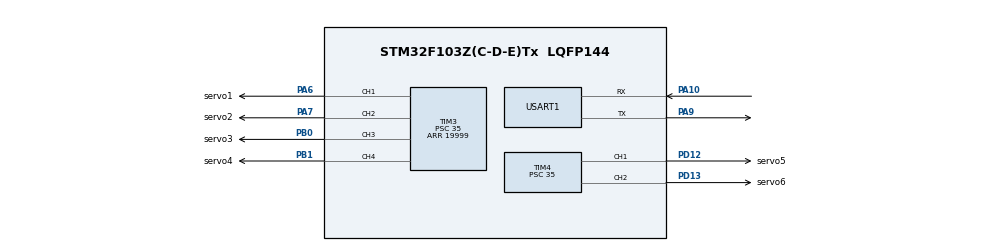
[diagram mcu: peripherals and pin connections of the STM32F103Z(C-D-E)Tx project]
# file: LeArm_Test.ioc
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Mcu.Family=STM32F1
Mcu.Name=STM32F103Z(C-D-E)Tx
Mcu.Package=LQFP144
NVIC.PriorityGroup=NVIC_PRIORITYGROUP_4
NVIC.USART1_IRQn=true\:0\:0\:false\:false\:true\:true\:true
OSC_IN.Mode=HSE-External-Oscillator
OSC_IN.Signal=RCC_OSC_IN
OSC_OUT.Mode=HSE-External-Oscillator
OSC_OUT.Signal=RCC_OSC_OUT
PA10.Mode=Asynchronous
PA10.Signal=USART1_RX
PA13.Mode=Serial_Wire
PA13.Signal=SYS_JTMS-SWDIO
PA14.Mode=Serial_Wire
PA14.Signal=SYS_JTCK-SWCLK
PA6.GPIO_Label=servo1
PA6.Signal=S_TIM3_CH1
PA7.GPIO_Label=servo2
PA7.Signal=S_TIM3_CH2
PA9.Mode=Asynchronous
PA9.Signal=USART1_TX
PB0.GPIO_Label=servo3
PB0.Signal=S_TIM3_CH3
PB1.GPIO_Label=servo4
PB1.Signal=S_TIM3_CH4
PD12.GPIO_Label=servo5
PD12.Signal=S_TIM4_CH1
PD13.GPIO_Label=servo6
PD13.Signal=S_TIM4_CH2
ProjectManager.HeapSize=0x200
ProjectManager.StackSize=0x400
ProjectManager.TargetToolchain=MDK-ARM V5.32
RCC.AHBCLKDivider=RCC_SYSCLK_DIV2
RCC.AHBFreq_Value=36000000
RCC.APB1Freq_Value=36000000
RCC.APB1TimFreq_Value=36000000
RCC.APB2Freq_Value=36000000
RCC.APB2TimFreq_Value=36000000
RCC.HCLKFreq_Value=36000000
RCC.PLLMUL=RCC_PLL_MUL9
RCC.PLLSourceVirtual=RCC_PLLSOURCE_HSE
RCC.SYSCLKFreq_VALUE=72000000
RCC.SYSCLKSource=RCC_SYSCLKSOURCE_PLLCLK
RCC.USBFreq_Value=72000000
SH.S_TIM3_CH1.0=TIM3_CH1,PWM Generation1 CH1
SH.S_TIM3_CH2.0=TIM3_CH2,PWM Generation2 CH2
SH.S_TIM3_CH3.0=TIM3_CH3,PWM Generation3 CH3
SH.S_TIM3_CH4.0=TIM3_CH4,PWM Generation4 CH4
SH.S_TIM4_CH1.0=TIM4_CH1,PWM Generation1 CH1
SH.S_TIM4_CH2.0=TIM4_CH2,PWM Generation2 CH2
TIM3.Channel-PWM\ Generation1\ CH1=TIM_CHANNEL_1
TIM3.Channel-PWM\ Generation2\ CH2=TIM_CHANNEL_2
TIM3.Channel-PWM\ Generation3\ CH3=TIM_CHANNEL_3
TIM3.Channel-PWM\ Generation4\ CH4=TIM_CHANNEL_4
TIM3.Period=19999
TIM3.Prescaler=35
TIM3.Pulse-PWM\ Generation1\ CH1=1400
TIM3.Pulse-PWM\ Generation2\ CH2=1500
TIM3.Pulse-PWM\ Generation3\ CH3=1056
TIM3.Pulse-PWM\ Generation4\ CH4=1056
TIM4.Channel-PWM\ Generation1\ CH1=TIM_CHANNEL_1
TIM4.Channel-PWM\ Generation2\ CH2=TIM_CHANNEL_2
TIM4.Period=19999
TIM4.Prescaler=35
TIM4.Pulse-PWM\ Generation1\ CH1=1500
TIM4.Pulse-PWM\ Generation2\ CH2=1500
USART1.VirtualMode=VM_ASYNC
VP_TIM3_VS_ClockSourceINT.Mode=Internal
VP_TIM4_VS_ClockSourceINT.Mode=Internal
board=custom

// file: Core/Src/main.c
/* USER CODE BEGIN Header */
/**
  ******************************************************************************
  * @file           : main.c
  * @brief          : Main program body
  ******************************************************************************
  * @attention
  *
  * <h2><center>&copy; Copyright (c) 2026 STMicroelectronics.
  * All rights reserved.</center></h2>
  *
  * This software component is licensed by ST under BSD 3-Clause license,
  * the "License"; You may not use this file except in compliance with the
  * License. You may obtain a copy of the License at:
  *                        opensource.org/licenses/BSD-3-Clause
  *
  ******************************************************************************
  */
/* USER CODE END Header */
#include "main.h"

/* USER CODE BEGIN Includes */
#include "learm_protocol.h"
#include "learm_servo.h"
/* USER CODE END Includes */

/* USER CODE BEGIN PD */
#define LEARM_SERVO_UPDATE_MS  20U
#define LEARM_PWM_TICK_HZ      1000000U
/* USER CODE END PD */

TIM_HandleTypeDef htim3;
TIM_HandleTypeDef htim4;

UART_HandleTypeDef huart1;

void SystemClock_Config(void);
static void MX_GPIO_Init(void);
static void MX_TIM3_Init(void);
static void MX_TIM4_Init(void);
static void MX_USART1_UART_Init(void);
static uint32_t LeArm_GetApb1TimerPrescaler(void);

int main(void)
{
  /* USER CODE BEGIN 1 */
  uint32_t lastServoTick;
  /* USER CODE END 1 */

  /* MCU Configuration--------------------------------------------------------*/

  /* Reset of all peripherals, Initializes the Flash interface and the Systick. */
  HAL_Init();

  /* Configure the system clock */
  SystemClock_Config();

  /* Initialize all configured peripherals */
  MX_GPIO_Init();
  MX_USART1_UART_Init();
  MX_TIM3_Init();
  MX_TIM4_Init();
  /* USER CODE BEGIN 2 */
  LeArm_ServoInit();
  LeArm_ProtocolInit(&huart1);
  lastServoTick = HAL_GetTick();
  /* USER CODE END 2 */

  /* Infinite loop */
  while (1)
  {

    /* USER CODE BEGIN 3 */
    LeArm_ProtocolTask();

    if ((uint32_t)(HAL_GetTick() - lastServoTick) >= LEARM_SERVO_UPDATE_MS)
    {
      lastServoTick += LEARM_SERVO_UPDATE_MS;
      LeArm_ServoUpdate20ms();
    }
  }
  /* USER CODE END 3 */
}

static uint32_t LeArm_GetApb1TimerPrescaler(void)
{
  uint32_t timerClockHz = HAL_RCC_GetPCLK1Freq();

  /* STM32F1 timers run at twice PCLK1 whenever APB1 is prescaled. */
  if ((RCC->CFGR & RCC_CFGR_PPRE1) != 0U)
  {
    timerClockHz *= 2U;
  }

  if ((timerClockHz < LEARM_PWM_TICK_HZ) ||
    ((timerClockHz % LEARM_PWM_TICK_HZ) != 0U))
  {
    Error_Handler();
  }

  return (timerClockHz / LEARM_PWM_TICK_HZ) - 1U;
}

void SystemClock_Config(void)
{
  RCC_OscInitTypeDef RCC_OscInitStruct = {0};
  RCC_ClkInitTypeDef RCC_ClkInitStruct = {0};

  /** Initializes the RCC Oscillators according to the specified parameters
  * in the RCC_OscInitTypeDef structure.
  */
  RCC_OscInitStruct.OscillatorType = RCC_OSCILLATORTYPE_HSE;
  RCC_OscInitStruct.HSEState = RCC_HSE_ON;
  RCC_OscInitStruct.HSEPredivValue = RCC_HSE_PREDIV_DIV1;
  RCC_OscInitStruct.HSIState = RCC_HSI_ON;
  RCC_OscInitStruct.PLL.PLLState = RCC_PLL_ON;
  RCC_OscInitStruct.PLL.PLLSource = RCC_PLLSOURCE_HSE;
  RCC_OscInitStruct.PLL.PLLMUL = RCC_PLL_MUL9;
  if (HAL_RCC_OscConfig(&RCC_OscInitStruct) != HAL_OK)
  {
    /* Keep the PWM outputs available on boards with a missing or failed HSE. */
    RCC_OscInitStruct = (RCC_OscInitTypeDef){0};
    RCC_OscInitStruct.OscillatorType = RCC_OSCILLATORTYPE_HSE | RCC_OSCILLATORTYPE_HSI;
    RCC_OscInitStruct.HSEState = RCC_HSE_OFF;
    RCC_OscInitStruct.HSIState = RCC_HSI_ON;
    RCC_OscInitStruct.HSICalibrationValue = RCC_HSICALIBRATION_DEFAULT;
    RCC_OscInitStruct.PLL.PLLState = RCC_PLL_OFF;
    if (HAL_RCC_OscConfig(&RCC_OscInitStruct) != HAL_OK)
    {
      Error_Handler();
    }

    RCC_ClkInitStruct = (RCC_ClkInitTypeDef){0};
    RCC_ClkInitStruct.ClockType = RCC_CLOCKTYPE_HCLK | RCC_CLOCKTYPE_SYSCLK |
      RCC_CLOCKTYPE_PCLK1 | RCC_CLOCKTYPE_PCLK2;
    RCC_ClkInitStruct.SYSCLKSource = RCC_SYSCLKSOURCE_HSI;
    RCC_ClkInitStruct.AHBCLKDivider = RCC_SYSCLK_DIV1;
    RCC_ClkInitStruct.APB1CLKDivider = RCC_HCLK_DIV1;
    RCC_ClkInitStruct.APB2CLKDivider = RCC_HCLK_DIV1;
    if (HAL_RCC_ClockConfig(&RCC_ClkInitStruct, FLASH_LATENCY_0) != HAL_OK)
    {
      Error_Handler();
    }
    return;
  }
  /** Initializes the CPU, AHB and APB buses clocks
  */
  RCC_ClkInitStruct.ClockType = RCC_CLOCKTYPE_HCLK|RCC_CLOCKTYPE_SYSCLK
                              |RCC_CLOCKTYPE_PCLK1|RCC_CLOCKTYPE_PCLK2;
  RCC_ClkInitStruct.SYSCLKSource = RCC_SYSCLKSOURCE_PLLCLK;
  RCC_ClkInitStruct.AHBCLKDivider = RCC_SYSCLK_DIV2;
  RCC_ClkInitStruct.APB1CLKDivider = RCC_HCLK_DIV1;
  RCC_ClkInitStruct.APB2CLKDivider = RCC_HCLK_DIV1;

  if (HAL_RCC_ClockConfig(&RCC_ClkInitStruct, FLASH_LATENCY_2) != HAL_OK)
  {
    Error_Handler();
  }
}

static void MX_TIM3_Init(void)
{

  TIM_ClockConfigTypeDef sClockSourceConfig = {0};
  TIM_MasterConfigTypeDef sMasterConfig = {0};
  TIM_OC_InitTypeDef sConfigOC = {0};

  htim3.Instance = TIM3;
  htim3.Init.Prescaler = LeArm_GetApb1TimerPrescaler();
  htim3.Init.CounterMode = TIM_COUNTERMODE_UP;
  htim3.Init.Period = 19999;
  htim3.Init.ClockDivision = TIM_CLOCKDIVISION_DIV1;
  htim3.Init.AutoReloadPreload = TIM_AUTORELOAD_PRELOAD_DISABLE;
  if (HAL_TIM_Base_Init(&htim3) != HAL_OK)
  {
    Error_Handler();
  }
  sClockSourceConfig.ClockSource = TIM_CLOCKSOURCE_INTERNAL;
  if (HAL_TIM_ConfigClockSource(&htim3, &sClockSourceConfig) != HAL_OK)
  {
    Error_Handler();
  }
  if (HAL_TIM_PWM_Init(&htim3) != HAL_OK)
  {
    Error_Handler();
  }
  sMasterConfig.MasterOutputTrigger = TIM_TRGO_RESET;
  sMasterConfig.MasterSlaveMode = TIM_MASTERSLAVEMODE_DISABLE;
  if (HAL_TIMEx_MasterConfigSynchronization(&htim3, &sMasterConfig) != HAL_OK)
  {
    Error_Handler();
  }
  sConfigOC.OCMode = TIM_OCMODE_PWM1;
  sConfigOC.OCPolarity = TIM_OCPOLARITY_HIGH;
  sConfigOC.OCFastMode = TIM_OCFAST_DISABLE;
  sConfigOC.Pulse = 1400;
  if (HAL_TIM_PWM_ConfigChannel(&htim3, &sConfigOC, TIM_CHANNEL_1) != HAL_OK)
  {
    Error_Handler();
  }
  sConfigOC.Pulse = 1500;
  if (HAL_TIM_PWM_ConfigChannel(&htim3, &sConfigOC, TIM_CHANNEL_2) != HAL_OK)
  {
    Error_Handler();
  }
  sConfigOC.Pulse = 1056;
  if (HAL_TIM_PWM_ConfigChannel(&htim3, &sConfigOC, TIM_CHANNEL_3) != HAL_OK)
  {
    Error_Handler();
  }
  sConfigOC.Pulse = 1056;
  if (HAL_TIM_PWM_ConfigChannel(&htim3, &sConfigOC, TIM_CHANNEL_4) != HAL_OK)
  {
    Error_Handler();
  }
  HAL_TIM_MspPostInit(&htim3);

}

static void MX_TIM4_Init(void)
{

  TIM_ClockConfigTypeDef sClockSourceConfig = {0};
  TIM_MasterConfigTypeDef sMasterConfig = {0};
  TIM_OC_InitTypeDef sConfigOC = {0};

  htim4.Instance = TIM4;
  htim4.Init.Prescaler = LeArm_GetApb1TimerPrescaler();
  htim4.Init.CounterMode = TIM_COUNTERMODE_UP;
  htim4.Init.Period = 19999;
  htim4.Init.ClockDivision = TIM_CLOCKDIVISION_DIV1;
  htim4.Init.AutoReloadPreload = TIM_AUTORELOAD_PRELOAD_DISABLE;
  if (HAL_TIM_Base_Init(&htim4) != HAL_OK)
  {
    Error_Handler();
  }
  sClockSourceConfig.ClockSource = TIM_CLOCKSOURCE_INTERNAL;
  if (HAL_TIM_ConfigClockSource(&htim4, &sClockSourceConfig) != HAL_OK)
  {
    Error_Handler();
  }
  if (HAL_TIM_PWM_Init(&htim4) != HAL_OK)
  {
    Error_Handler();
  }
  sMasterConfig.MasterOutputTrigger = TIM_TRGO_RESET;
  sMasterConfig.MasterSlaveMode = TIM_MASTERSLAVEMODE_DISABLE;
  if (HAL_TIMEx_MasterConfigSynchronization(&htim4, &sMasterConfig) != HAL_OK)
  {
    Error_Handler();
  }
  sConfigOC.OCMode = TIM_OCMODE_PWM1;
  sConfigOC.Pulse = 1500;
  sConfigOC.OCPolarity = TIM_OCPOLARITY_HIGH;
  sConfigOC.OCFastMode = TIM_OCFAST_DISABLE;
  if (HAL_TIM_PWM_ConfigChannel(&htim4, &sConfigOC, TIM_CHANNEL_1) != HAL_OK)
  {
    Error_Handler();
  }
  if (HAL_TIM_PWM_ConfigChannel(&htim4, &sConfigOC, TIM_CHANNEL_2) != HAL_OK)
  {
    Error_Handler();
  }
  HAL_TIM_MspPostInit(&htim4);

}

static void MX_USART1_UART_Init(void)
{

  huart1.Instance = USART1;
  huart1.Init.BaudRate = 115200;
  huart1.Init.WordLength = UART_WORDLENGTH_8B;
  huart1.Init.StopBits = UART_STOPBITS_1;
  huart1.Init.Parity = UART_PARITY_NONE;
  huart1.Init.Mode = UART_MODE_TX_RX;
  huart1.Init.HwFlowCtl = UART_HWCONTROL_NONE;
  huart1.Init.OverSampling = UART_OVERSAMPLING_16;
  if (HAL_UART_Init(&huart1) != HAL_OK)
  {
    Error_Handler();
  }

}

static void MX_GPIO_Init(void)
{

  /* GPIO Ports Clock Enable */
  __HAL_RCC_GPIOD_CLK_ENABLE();
  __HAL_RCC_GPIOA_CLK_ENABLE();
  __HAL_RCC_GPIOB_CLK_ENABLE();

}

void Error_Handler(void)
{
  __disable_irq();
  while (1)
  {
  }
}

/************************ (C) COPYRIGHT STMicroelectronics *****END OF FILE****/
